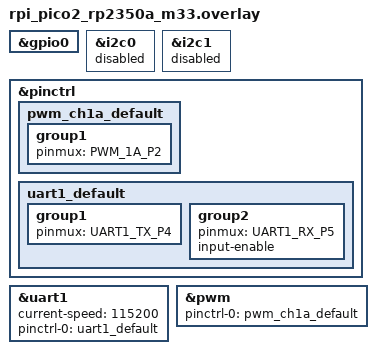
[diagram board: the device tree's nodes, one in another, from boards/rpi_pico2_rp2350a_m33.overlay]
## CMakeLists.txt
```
cmake_minimum_required(VERSION 3.20.0)

find_package(Zephyr REQUIRED HINTS $ENV{ZEPHYR_BASE})
project(blueline)

target_sources(app PRIVATE
	src/main.c
	src/fsm_main.c
	src/pico_io.c
	src/bt_uart.c
	src/bt_fsm.c
	src/bm_83.c
	src/slic.c
	src/ring.c
)
```

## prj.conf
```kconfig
CONFIG_GPIO=y
CONFIG_LOG=y
CONFIG_THREAD_NAME=y
CONFIG_PRINTK=y
CONFIG_SERIAL=y
CONFIG_UART_INTERRUPT_DRIVEN=y
CONFIG_PWM=y
CONFIG_EVENTS=y

# Log buffer: BM83 sends event bursts (one every ~5 ms) faster than the
# 115200 baud console can print them; 1024 (default) drops log messages
CONFIG_LOG_BUFFER_SIZE=8192
```

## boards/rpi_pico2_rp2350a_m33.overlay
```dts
/*
 * blueline - devicetree overlay for rpi_pico2/rp2350a/m33
 *
 * Only changes to the stock board devicetree are listed here. The stock board
 * already provides: gpio0, console on uart0 (GPIO0 TX / GPIO1 RX) and the user
 * LED led0 on GPIO25.
 *
 * GPIO usage of this project. The pins are configured at runtime in
 * src/pico_io.c, not through devicetree nodes:
 *
 *   GPIO2   POT_FWD_PIN      SLIC, PWM1 output (slice 1 A), 25 Hz, high = ringer off (src/ring.c)
 *   GPIO3   POT_PDOWN_N_PIN  SLIC power down, tristate after init (src/slic.c)
 *   GPIO6   BT_RST_N_PIN     output (BM83 reset, src/bm_83.c), low after init
 *   GPIO7   RING_MODE_PIN    SLIC, output, low after init (src/slic.c)
 *   GPIO8   BT_MFB_PIN       output (BM83 MFB, src/bm_83.c), low after init
 *   GPIO11  SHK_RISING_PIN   input, no pulls, IRQ on rising edge
 *   GPIO12  SHK_FALLING_PIN  input, no pulls, IRQ on falling edge
 *   GPIO25  PICO_IO_LED_PIN  output, user LED, high = on
 *
 * UART1 to the Microchip BM83 Bluetooth module (src/bt_uart.c):
 *
 *   GPIO4   UART1 TX  (RP2350 -> BM83)
 *   GPIO5   UART1 RX  (BM83 -> RP2350)
 *   115200 baud, 8N1, no flow control
 */

/* pico_io.c uses gpio0 directly (DT_NODELABEL(gpio0)) */
&gpio0 {
	status = "okay";
};

/* The stock board enables i2c0 (GPIO4/5) and i2c1 (GPIO6/7). These pins are
 * used here for UART1 and RING_MODE, so both I2C controllers are disabled. */
&i2c0 {
	status = "disabled";
};

&i2c1 {
	status = "disabled";
};

&pinctrl {
	/* ringer PWM: PWM slice 1 channel A on GP2 (POT_FWD) */
	pwm_ch1a_default: pwm_ch1a_default {
		group1 {
			pinmux = <PWM_1A_P2>;
		};
	};

	uart1_default: uart1_default {
		group1 {
			pinmux = <UART1_TX_P4>;
		};
		group2 {
			pinmux = <UART1_RX_P5>;
			input-enable;
		};
	};
};

/* BM83 link, no hw-flow-control property = no RTS/CTS */
&uart1 {
	status = "okay";
	current-speed = <115200>;
	pinctrl-0 = <&uart1_default>;
	pinctrl-names = "default";
};

/* Ringer PWM (src/ring.c). Replaces the board default pinctrl (PWM 4B on the
 * user LED GP25), so GP25 stays a GPIO. */
&pwm {
	status = "okay";
	pinctrl-0 = <&pwm_ch1a_default>;
	pinctrl-names = "default";
};
```

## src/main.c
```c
/*
 * blueline - main.c
 * Target: Raspberry Pi Pico 2 (RP2350), Zephyr RTOS
 * Initialises the I/O and creates all application threads.
 */

#include <zephyr/kernel.h>
#include <zephyr/logging/log.h>

#include "main.h"
#include "fsm_main.h"
#include "bt_fsm.h"
#include "pico_io.h"
#include "bt_uart.h"
#include "bm_83.h"
#include "slic.h"
#include "ring.h"

LOG_MODULE_REGISTER(main, LOG_LEVEL_INF);

/* ---- fsm_thread -------------------------------------------------------- */

K_THREAD_STACK_DEFINE(fsm_thread_stack, FSM_THREAD_STACK_SIZE);
static struct k_thread fsm_thread_data;
static k_tid_t fsm_thread_id;

/* ---- bt_fsm_thread ----------------------------------------------------- */

K_THREAD_STACK_DEFINE(bt_fsm_thread_stack, BT_FSM_THREAD_STACK_SIZE);
static struct k_thread bt_fsm_thread_data;
static k_tid_t bt_fsm_thread_id;

/* ---- bt_rx_thread ------------------------------------------------------ */

K_THREAD_STACK_DEFINE(bt_rx_thread_stack, BT_RX_THREAD_STACK_SIZE);
static struct k_thread bt_rx_thread_data;
static k_tid_t bt_rx_thread_id;

/* ---- ring_thread ------------------------------------------------------- */

K_THREAD_STACK_DEFINE(ring_thread_stack, RING_THREAD_STACK_SIZE);
static struct k_thread ring_thread_data;
static k_tid_t ring_thread_id;

/* ---- further threads will be added here -------------------------------- */

int main(void)
{
	LOG_INF("blueline starting");

	/* first: drive POT_FWD (GP2, PWM1) high as early as possible */
	if (ring_init() < 0) {
		LOG_ERR("ringer PWM init failed, stopping");
		return -1;
	}

	if (pico_io_init() < 0) {
		LOG_ERR("I/O init failed, stopping");
		return -1;
	}

	if (bt_uart_init() < 0) {
		LOG_ERR("BM83 UART init failed, stopping");
		return -1;
	}

	if (slic_init() < 0) {
		LOG_ERR("SLIC init failed, stopping");
		return -1;
	}


	fsm_thread_id = k_thread_create(&fsm_thread_data,
					fsm_thread_stack,
					K_THREAD_STACK_SIZEOF(fsm_thread_stack),
					fsm_main,
					NULL, NULL, NULL,
					FSM_THREAD_PRIORITY, 0, K_NO_WAIT);
	k_thread_name_set(fsm_thread_id, "fsm_thread");

	bt_fsm_thread_id = k_thread_create(&bt_fsm_thread_data,
					   bt_fsm_thread_stack,
					   K_THREAD_STACK_SIZEOF(bt_fsm_thread_stack),
					   bt_fsm_main,
					   NULL, NULL, NULL,
					   BT_FSM_THREAD_PRIORITY, 0, K_NO_WAIT);
	k_thread_name_set(bt_fsm_thread_id, "bt_fsm_thread");

	bt_rx_thread_id = k_thread_create(&bt_rx_thread_data,
					  bt_rx_thread_stack,
					  K_THREAD_STACK_SIZEOF(bt_rx_thread_stack),
					  bt_rx_main,
					  NULL, NULL, NULL,
					  BT_RX_THREAD_PRIORITY, 0, K_NO_WAIT);
	k_thread_name_set(bt_rx_thread_id, "bt_rx_thread");

	ring_thread_id = k_thread_create(&ring_thread_data,
					 ring_thread_stack,
					 K_THREAD_STACK_SIZEOF(ring_thread_stack),
					 generate_ring,
					 NULL, NULL, NULL,
					 RING_THREAD_PRIORITY, 0, K_NO_WAIT);
	k_thread_name_set(ring_thread_id, "ring_thread");

	/* BM83 power-up runs last: bt_rx_thread is already running and shows
	 * the BM83 responses (ACKs, status events) as they arrive. */
	if (IS_ENABLED(BT_UART_TX_DISABLE)) {
		/* BM83 is being programmed through J3: leave it alone */
		LOG_WRN("BT_UART_TX_DISABLE: bm83_init() skipped, GP6/GP8 not driven");
	} else if (bm83_init() < 0) {
		LOG_ERR("BM83 init failed");
		return -1;
	}

	/* main returns; the application threads keep running */
	return 0;
}
```

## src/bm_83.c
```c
/*
 * blueline - bm_83.c
 * Microchip BM83 Bluetooth module: control signals, power-up sequence and
 * commands sent over the UART (bt_uart.c).
 *
 * Power-up sequence (bm83_init):
 *   bt_rst_n = low, bt_mfb = low
 *   100 ms -> bt_mfb   = high
 *    20 ms -> bt_rst_n = high (BM83 out of reset)
 *   500 ms
 *   MMI action 0x51 (power on button press)
 *   MMI action 0x52 (power on button release)
 *   Read_BTM_Version (firmware version)
 *   MMI action 0x5D (enter pairing mode)
 *   bt_mfb = low
 *
 * MFB handshake: in host MCU mode MFB is the BM83 UART_RX_IND input
 * ("UART data from the MCU follows"), see Audio UART Command Set 4.1/4.4/4.5.
 *   command:    MFB high, >= 3 ms, send, wait for Command_ACK (max 200 ms),
 *               MFB low
 *   Event_ACK:  MFB high, >= 3 ms, send, MFB low (no reply)
 * Commands (main thread) and Event_ACKs (bt_rx_thread) can overlap, so MFB
 * is reference counted: high with the first user, low after the last one.
 *
 * The BM83 must be programmed with a host MCU mode configuration (UART
 * command interface enabled), otherwise it ignores all UART commands.
 */

#include <string.h>

#include <zephyr/kernel.h>
#include <zephyr/device.h>
#include <zephyr/drivers/gpio.h>
#include <zephyr/logging/log.h>

#include "bm_83.h"
#include "bt_uart.h"
#include "bt_fsm.h"

LOG_MODULE_REGISTER(bm_83, LOG_LEVEL_INF);

static const struct device *const gpio0 = DEVICE_DT_GET(DT_NODELABEL(gpio0));

/* ---- MFB handshake ----------------------------------------------------- */

K_MUTEX_DEFINE(mfb_mutex);
static uint8_t mfb_users;	/* senders that currently need MFB high */
static int64_t mfb_rise_ticks;	/* uptime when MFB went high */

/* MFB high (if not already) without waiting for the lead time */
static void bm83_mfb_raise(void)
{
	k_mutex_lock(&mfb_mutex, K_FOREVER);
	if (mfb_users++ == 0) {
		gpio_pin_set(gpio0, BT_MFB_PIN, 1);
		mfb_rise_ticks = k_uptime_ticks();
	}
	k_mutex_unlock(&mfb_mutex);
}

/* MFB high and wait until it has been high for BM83_MFB_LEAD_MS */
static void bm83_mfb_get(void)
{
	int64_t ready;
	int64_t now;

	bm83_mfb_raise();

	k_mutex_lock(&mfb_mutex, K_FOREVER);
	ready = mfb_rise_ticks + k_ms_to_ticks_ceil64(BM83_MFB_LEAD_MS);
	k_mutex_unlock(&mfb_mutex);

	now = k_uptime_ticks();
	if (now < ready) {
		k_sleep(K_TICKS(ready - now));
	}
}

/* Release MFB: low again when no other sender needs it */
static void bm83_mfb_put(void)
{
	k_mutex_lock(&mfb_mutex, K_FOREVER);
	if (mfb_users > 0 && --mfb_users == 0) {
		gpio_pin_set(gpio0, BT_MFB_PIN, 0);
	}
	k_mutex_unlock(&mfb_mutex);
}

/* ---- Command_ACK ------------------------------------------------------- */

/* Only one command at a time waits for its Command_ACK */
K_MUTEX_DEFINE(cmd_mutex);
K_SEM_DEFINE(cmd_ack_sem, 0, 1);
static bool cmd_ack_pending;
static uint8_t cmd_ack_id;	/* opcode of the command waiting for its ACK */
static uint8_t cmd_ack_status;

void bm83_command_ack_received(uint8_t cmd_id, uint8_t status)
{
	if (cmd_ack_pending && cmd_id == cmd_ack_id) {
		cmd_ack_status = status;
		cmd_ack_pending = false;

		/* Make_Call result goes to bt_fsm from here, so it is queued
		 * before the Call_Status events that follow the ACK */
		if (cmd_id == BM83_CMD_MAKE_CALL) {
			bt_fsm_post_event(status == BM83_ACK_COMMAND_COMPLETE ?
					  BT_EVT_CALL_ACK_OK : BT_EVT_CALL_ACK_FAIL);
		}

		k_sem_give(&cmd_ack_sem);
	}
}

/* ---- commands ---------------------------------------------------------- */

/* Build a frame for opcode and params */
static int bm83_build(uint8_t *frame, size_t size, uint8_t opcode,
		      const uint8_t *params, uint8_t num_params)
{
	int len;

	len = bt_uart_build_frame(frame, size, opcode, params, num_params);
	if (len < 0) {
		LOG_ERR("command 0x%02X: cannot build frame (%d)", opcode, len);
	}
	return len;
}

/* Send a command with the MFB handshake and wait for its Command_ACK.
 * Must not be called from bt_rx_thread (it delivers the Command_ACK).
 * Returns 0 on "command complete", -EIO for another ACK status,
 * -ETIMEDOUT if no Command_ACK arrives within BM83_CMD_ACK_TIMEOUT_MS. */
static int bm83_send_cmd(uint8_t opcode, const uint8_t *params, uint8_t num_params)
{
	uint8_t frame[BT_FRAME_MAX_LEN];
	int len;
	int ret;

	len = bm83_build(frame, sizeof(frame), opcode, params, num_params);
	if (len < 0) {
		return len;
	}

	k_mutex_lock(&cmd_mutex, K_FOREVER);

	k_sem_reset(&cmd_ack_sem);
	cmd_ack_id = opcode;
	cmd_ack_pending = true;

	bm83_mfb_get();
	bt_uart_send(frame, len);
	ret = k_sem_take(&cmd_ack_sem, K_MSEC(BM83_CMD_ACK_TIMEOUT_MS));
	bm83_mfb_put();

	cmd_ack_pending = false;

	if (ret != 0) {
		LOG_WRN("command 0x%02X: no Command_ACK within %d ms",
			opcode, BM83_CMD_ACK_TIMEOUT_MS);
		ret = -ETIMEDOUT;
	} else if (cmd_ack_status != BM83_ACK_COMMAND_COMPLETE) {
		LOG_WRN("command 0x%02X: Command_ACK status 0x%02X",
			opcode, cmd_ack_status);
		ret = -EIO;
	}

	k_mutex_unlock(&cmd_mutex);
	return ret;
}

int bm83_mmi_action(uint8_t action)
{
	const uint8_t params[] = { BM83_DATABASE_INDEX, action };

	LOG_INF("tx: MMI action 0x%02X", action);
	return bm83_send_cmd(BM83_CMD_MMI_ACTION, params, sizeof(params));
}

int bm83_enter_pairing(void)
{
	LOG_INF("tx: enter pairing mode");
	return bm83_mmi_action(BM83_MMI_ENTER_PAIRING);
}

int bm83_read_link_status(void)
{
	const uint8_t params[] = { 0x00 };	/* reserved */

	LOG_INF("tx: Read_Link_Status");
	return bm83_send_cmd(BM83_CMD_READ_LINK_STATUS, params, sizeof(params));
}

/* Print Read_Link_Status_Reply: device state, then per database the connected
 * profiles, play status and stream status */
static void bm83_log_link_status(const uint8_t *params, uint8_t num_params)
{
	static const char *const states[] = {
		"power off", "pairing", "standby", "connected (HF only)",
		"connected (A2DP only)", "connected (SPP only)",
		"connected (multi-profile)",
	};

	if (num_params < 3) {
		return;
	}

	LOG_INF("link status: device state 0x%02X %s", params[0],
		params[0] < ARRAY_SIZE(states) ? states[params[0]] : "unknown");

	for (uint8_t db = 0; db < 2; db++) {
		uint8_t con = params[1 + db];

		LOG_INF("link status: database %u: HF %s, A2DP %s/%s, AVRCP %s, SPP %s"
			" (0x%02X), play 0x%02X, stream 0x%02X",
			db,
			(con & BIT(3)) ? "yes" : "no",
			(con & BIT(0)) ? "sig" : "-",
			(con & BIT(1)) ? "stream" : "-",
			(con & BIT(2)) ? "yes" : "no",
			(con & BIT(4)) ? "yes" : "no",
			con,
			num_params > 3 + db ? params[3 + db] : 0,
			num_params > 5 + db ? params[5 + db] : 0);
	}
}

int bm83_end_call(void)
{
	LOG_INF("tx: end call");
	return bm83_mmi_action(BM83_MMI_END_CALL);
}

int bm83_accept_call(void)
{
	LOG_INF("tx: accept call");
	return bm83_mmi_action(BM83_MMI_ACCEPT_CALL);
}

int bm83_make_call(const char *number, uint8_t len)
{
	uint8_t params[1 + BM83_PHONE_NUMBER_MAX];

	if (len > BM83_PHONE_NUMBER_MAX) {
		LOG_ERR("Make_Call: number too long (%u digits)", len);
		return -EINVAL;
	}

	params[0] = BM83_DATABASE_INDEX;
	memcpy(&params[1], number, len);

	LOG_INF("tx: Make_Call \"%.*s\"", len, number);
	return bm83_send_cmd(BM83_CMD_MAKE_CALL, params, 1 + len);
}

void bm83_handle_event(uint8_t opcode, const uint8_t *params, uint8_t num_params)
{
	switch (opcode) {
	case BM83_EVT_BTM_STATUS:
		/* phone connected (HF or A2DP link): set the output gain */
		if (num_params >= 1 &&
		    (params[0] == BM83_STATUS_HF_LINK ||
		     params[0] == BM83_STATUS_A2DP_LINK)) {
			bm83_link_established();
		}
		break;
	case BM83_EVT_LINK_STATUS_REPLY:
		bm83_log_link_status(params, num_params);
		break;
	case BM83_EVT_CALL_STATUS:
		/* params: data_base_index, call status */
		if (num_params < 2) {
			break;
		}
		if (params[1] == BM83_CALL_OUTGOING || params[1] == BM83_CALL_ACTIVE) {
			bt_fsm_post_event(BT_EVT_CALL_OUTGOING);
		} else if (params[1] == BM83_CALL_IDLE) {
			bt_fsm_post_event(BT_EVT_CALL_IDLE);
		} else if (params[1] == BM83_CALL_INCOMING) {
			bt_fsm_post_event(BT_EVT_CALL_INCOMING);
		}
		break;
	default:
		break;
	}
}

int bm83_set_overall_gain(uint8_t mask, uint8_t type, uint8_t a2dp,
			  uint8_t hf, uint8_t line_in)
{
	const uint8_t params[] = { BM83_DATABASE_INDEX, mask, type,
				   a2dp, hf, line_in };

	LOG_INF("tx: Set_Overall_Gain mask 0x%02X type 0x%02X A2DP %u HF %u line-in %u",
		mask, type, a2dp, hf, line_in);
	return bm83_send_cmd(BM83_CMD_SET_OVERALL_GAIN, params, sizeof(params));
}

/* Runs in the system workqueue: may wait for the Command_ACK */
static void bm83_gain_work_handler(struct k_work *work)
{
	ARG_UNUSED(work);

	bm83_set_overall_gain(BM83_GAIN_MASK_A2DP | BM83_GAIN_MASK_HF,
			      BM83_GAIN_TYPE_ABS_LEVEL,
			      BM83_A2DP_GAIN_LEVEL, BM83_HF_GAIN_LEVEL, 0);
}

K_WORK_DEFINE(bm83_gain_work, bm83_gain_work_handler);

void bm83_link_established(void)
{
	k_work_submit(&bm83_gain_work);
}

int bm83_read_btm_version(uint8_t type)
{
	const uint8_t params[] = { type };

	LOG_INF("tx: Read_BTM_Version type 0x%02X", type);
	return bm83_send_cmd(BM83_CMD_READ_BTM_VERSION, params, sizeof(params));
}

int bm83_event_ack(uint8_t event_id)
{
	const uint8_t params[] = { event_id };
	uint8_t frame[BT_FRAME_MAX_LEN];
	int len;

	len = bm83_build(frame, sizeof(frame), BM83_CMD_EVENT_ACK,
			 params, sizeof(params));
	if (len < 0) {
		return len;
	}

	/* the BM83 does not answer an Event_ACK: MFB low right after sending */
	bm83_mfb_get();
	bt_uart_send(frame, len);
	bm83_mfb_put();

	LOG_DBG("tx: Event_ACK 0x%02X", event_id);
	return 0;
}

/* ---- init -------------------------------------------------------------- */

int bm83_init(void)
{
	int ret;

	if (!device_is_ready(gpio0)) {
		LOG_ERR("gpio0 not ready");
		return -ENODEV;
	}

	/* bt_rst_n: output, low (BM83 held in reset) */
	ret = gpio_pin_configure(gpio0, BT_RST_N_PIN, GPIO_OUTPUT_LOW);
	if (ret < 0) {
		LOG_ERR("bt_rst_n pin config failed (%d)", ret);
		return ret;
	}

	/* bt_mfb: output, low */
	ret = gpio_pin_configure(gpio0, BT_MFB_PIN, GPIO_OUTPUT_LOW);
	if (ret < 0) {
		LOG_ERR("bt_mfb pin config failed (%d)", ret);
		return ret;
	}

	/* MFB stays high from here through the power-up commands */
	k_msleep(BM83_MFB_HIGH_DELAY_MS);
	bm83_mfb_raise();

	k_msleep(BM83_RST_HIGH_DELAY_MS);
	gpio_pin_set(gpio0, BT_RST_N_PIN, 1);

	k_msleep(BM83_CMD_DELAY_MS);

	ret = bm83_mmi_action(BM83_MMI_POWER_ON_PRESS);
	if (ret == 0) {
		ret = bm83_mmi_action(BM83_MMI_POWER_ON_RELEASE);
	}
	if (ret == 0) {
		ret = bm83_read_btm_version(BM83_VERSION_FW);
	}
	if (ret == 0) {
		ret = bm83_enter_pairing();
	}

	/* end of the power-up sequence: MFB low unless an Event_ACK is going out */
	bm83_mfb_put();

	if (ret < 0) {
		return ret;
	}

	LOG_INF("BM83 initialised (GPIO%d bt_rst_n / GPIO%d bt_mfb)",
		BT_RST_N_PIN, BT_MFB_PIN);
	return 0;
}
```

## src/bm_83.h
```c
/*
 * blueline - bm_83.h
 * Microchip BM83 Bluetooth module: control signals, power-up sequence and
 * commands sent over the UART (bt_uart.c).
 */

#ifndef BM_83_H
#define BM_83_H

#include <stdint.h>
#include <zephyr/sys/util.h>

/* Pin assignment */
#define BT_RST_N_PIN   6   /* output, BM83 reset, active low */
#define BT_MFB_PIN     8   /* output, BM83 multi-function button */

/* Power-up sequence timing */
#define BM83_MFB_HIGH_DELAY_MS   100   /* init -> bt_mfb high */
#define BM83_RST_HIGH_DELAY_MS   20    /* bt_mfb high -> bt_rst_n high */
#define BM83_CMD_DELAY_MS        500   /* bt_rst_n high -> first command */

/* MFB handshake (Audio UART Command Set 4.4/4.5) */
#define BM83_MFB_LEAD_MS          3     /* bt_mfb high -> UART data (> 2 ms) */
#define BM83_CMD_ACK_TIMEOUT_MS   200   /* command -> Command_ACK */

/* Command opcodes */
#define BM83_CMD_MAKE_CALL       0x00
#define BM83_CMD_MMI_ACTION      0x02
#define BM83_CMD_READ_BTM_VERSION  0x08
#define BM83_CMD_READ_LINK_STATUS  0x0D
#define BM83_CMD_EVENT_ACK         0x14
#define BM83_CMD_SET_OVERALL_GAIN  0x23

/* Event opcodes */
#define BM83_EVT_COMMAND_ACK       0x00
#define BM83_EVT_BTM_STATUS        0x01
#define BM83_EVT_CALL_STATUS       0x02
#define BM83_EVT_LINK_STATUS_REPLY 0x1E

/* BTM_Status states that start the gain setting */
#define BM83_STATUS_HF_LINK        0x05   /* HF/HS link established */
#define BM83_STATUS_A2DP_LINK      0x06   /* A2DP link established */

/* Call_Status states */
#define BM83_CALL_IDLE             0x00   /* idle, no call */
#define BM83_CALL_INCOMING         0x02   /* incoming call */
#define BM83_CALL_OUTGOING         0x03   /* outgoing call */
#define BM83_CALL_ACTIVE           0x04   /* call active */

/* Database index of all commands with a Data_Base_Index parameter */
#define BM83_DATABASE_INDEX        0x00

/* Make_Call: maximum length of the phone number (ASCII digits) */
#define BM83_PHONE_NUMBER_MAX      19

/* Set_Overall_Gain: mask bits, type, levels */
#define BM83_GAIN_MASK_A2DP        BIT(0)
#define BM83_GAIN_MASK_HF          BIT(1)
#define BM83_GAIN_MASK_LINE_IN     BIT(2)
#define BM83_GAIN_TYPE_ABS_LEVEL   0x03   /* set absolute gain level 0..15 */
#define BM83_GAIN_LEVEL_MAX        0x0F

/* Gain levels set after the phone has connected (0..15) */
#define BM83_A2DP_GAIN_LEVEL       BM83_GAIN_LEVEL_MAX
#define BM83_HF_GAIN_LEVEL         BM83_GAIN_LEVEL_MAX

/* Command_ACK status */
#define BM83_ACK_COMMAND_COMPLETE  0x00

/* MMI actions */
#define BM83_MMI_POWER_ON_PRESS    0x51
#define BM83_MMI_POWER_ON_RELEASE  0x52
#define BM83_MMI_ENTER_PAIRING     0x5D   /* fast enter pairing mode (from non-off) */
#define BM83_MMI_ACCEPT_CALL       0x04   /* accept an incoming call */
#define BM83_MMI_END_CALL          0x06   /* end call / transfer audio to phone */

/* Read_BTM_Version types (reply: event 0x18 Read_BTM_Version_Reply) */
#define BM83_VERSION_UART          0x00
#define BM83_VERSION_FW            0x01

/* Initialise bt_rst_n and bt_mfb, run the power-up sequence, power the
 * BM83 on with MMI actions 0x51/0x52 and request its firmware version
 * (Read_BTM_Version) and put it into pairing mode. bt_mfb is low afterwards.
 * Blocks for about 650 ms.
 * Returns 0 on success, negative errno otherwise. */
int bm83_init(void);

/* Commands below are sent with the MFB handshake and wait for their
 * Command_ACK (max BM83_CMD_ACK_TIMEOUT_MS). They must not be called from
 * bt_rx_thread. Return 0 on "command complete", -EIO for another ACK status,
 * -ETIMEDOUT without ACK, other negative errno on errors. */

/* Send an MMI action command (opcode 0x02, data_base_index 0x00, action). */
int bm83_mmi_action(uint8_t action);

/* Put the BM83 into pairing mode (discoverable), MMI action 0x5D with a
 * pairing tone. Result: BTM_Status 0x01 (pairing), later 0x03 (pairing
 * successful) or 0x04 (pairing failed). */
int bm83_enter_pairing(void);

/* Set_Overall_Gain (opcode 0x23): data_base_index 0x00, mask (BM83_GAIN_MASK_*),
 * type (e.g. BM83_GAIN_TYPE_ABS_LEVEL), gain for A2DP, HF and line-in.
 * The phone may later change the gain again (AVRCP absolute volume). */
int bm83_set_overall_gain(uint8_t mask, uint8_t type, uint8_t a2dp,
			  uint8_t hf, uint8_t line_in);

/* Read_Link_Status (opcode 0x0D): the reply (event 0x1E) is decoded and
 * printed by bm83_handle_event(): device state and, per database, which
 * profiles (A2DP, AVRCP, HF, SPP) are connected. */
int bm83_read_link_status(void);

/* End the active call: MMI action 0x06 "End call / transfer audio to phone". */
int bm83_end_call(void);

/* Accept the incoming call: MMI action 0x04 "Accept an incoming call". */
int bm83_accept_call(void);

/* Make_Call (opcode 0x00): data_base_index 0x00, phone number as ASCII
 * digits (len <= BM83_PHONE_NUMBER_MAX). The Command_ACK result is also
 * posted to bt_fsm (BT_EVT_CALL_ACK_OK / BT_EVT_CALL_ACK_FAIL) by
 * bt_rx_thread. */
int bm83_make_call(const char *number, uint8_t len);

/* Called by bt_rx_thread for every received event except Command_ACK:
 * starts the gain setting when a link is established, forwards Call_Status
 * (incoming / outgoing / active / idle) to bt_fsm, prints Read_Link_Status_Reply. params[] are the event parameters. */
void bm83_handle_event(uint8_t opcode, const uint8_t *params, uint8_t num_params);

/* Called by bt_rx_thread when a link to the phone is established: sets
 * BM83_A2DP_GAIN_LEVEL / BM83_HF_GAIN_LEVEL from the system workqueue
 * (bt_rx_thread itself must not send commands). */
void bm83_link_established(void);

/* Send a Read_BTM_Version command (opcode 0x08) with the given type
 * (BM83_VERSION_UART or BM83_VERSION_FW). */
int bm83_read_btm_version(uint8_t type);

/* Acknowledge a received BM83 event (Event_ACK, opcode 0x14, param event_id).
 * Without it the BM83 waits 800 ms before it sends the next event
 * (Audio UART Command Set 4.5.2). Command_ACK events are not acknowledged.
 * Sent with the MFB handshake, does not wait for a reply.
 * Returns 0 on success, negative errno otherwise. */
int bm83_event_ack(uint8_t event_id);

/* Called by bt_rx_thread for every received Command_ACK: wakes up the
 * command waiting for it. */
void bm83_command_ack_received(uint8_t cmd_id, uint8_t status);

#endif /* BM_83_H */
```

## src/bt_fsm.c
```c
/*
 * blueline - bt_fsm.c
 * Bluetooth state machine running in bt_fsm_thread.
 *
 *   BT_IDLE            --BT_EVT_DIALCMPL-->       BT_MAKE_CALL
 *   BT_IDLE            --BT_EVT_CALL_INCOMING-->  BT_RING_MODE
 *   BT_RING_MODE       --BT_EVT_RING_PROTECT-->   BT_RING_BELL
 *   BT_RING_MODE       --BT_EVT_CALL_IDLE-->      BT_IDLE
 *   BT_RING_MODE       --BT_EVT_OFFHOOK-->        BT_OUT_ESTABLISHED  (RING_MODE low, MMI 0x04)
 *   BT_RING_BELL       --BT_EVT_OFFHOOK-->        BT_STOP_RING
 *   BT_RING_BELL       --BT_EVT_CALL_IDLE-->      BT_IDLE
 *   BT_STOP_RING       --BT_EVT_RING_PROTECT-->   BT_OUT_ESTABLISHED  (RING_MODE low, MMI 0x04)
 *   BT_STOP_RING       --BT_EVT_CALL_IDLE-->      BT_IDLE
 *   BT_MAKE_CALL       --BT_EVT_CALL_ACK_OK-->    BT_CALLER_WAIT
 *   BT_MAKE_CALL       --BT_EVT_CALL_ACK_FAIL-->  BT_NOHF
 *   BT_CALLER_WAIT     --BT_EVT_CALL_OUTGOING-->  BT_OUT_ESTABLISHED
 *   BT_CALLER_WAIT     --BT_EVT_MAIN_IDLE-->      BT_IDLE  (MMI 0x06 end call)
 *   BT_OUT_ESTABLISHED --BT_EVT_MAIN_IDLE-->      BT_IDLE  (MMI 0x06 end call)
 *   BT_OUT_ESTABLISHED --BT_EVT_CALL_IDLE-->      BT_IDLE
 *   every state except BT_IDLE  --BT_EVT_MAIN_IDLE-->  BT_IDLE
 *
 * Entry actions:
 *   BT_IDLE       RING_MODE_PIN low, ring_stop() (PWM_ON withdrawn)
 *   BT_MAKE_CALL  dialed_number_reg (fsm_main) as ASCII -> Make_Call (0x00)
 *   BT_RING_MODE  RING_MODE_PIN high, start ring_protect_timer (50 ms)
 *   BT_RING_BELL  ring_start() (PWM_ON: ring.c generates the cadence)
 *   BT_STOP_RING  ring_stop() (PWM_ON withdrawn, POT_FWD high at once),
 *                 start ring_protect_timer (50 ms)
 *
 * Event sources:
 *   BT_EVT_MAIN_IDLE      fsm_main, whenever it enters STATE_S0_IDLE
 *   BT_EVT_DIALCMPL       fsm_main, dialcmpl_timer expired in STATE_S1_OFFHOOK
 *   BT_EVT_CALL_ACK_OK    bt_rx_thread, Command_ACK of Make_Call, status 0x00
 *   BT_EVT_CALL_ACK_FAIL  bt_rx_thread, Command_ACK of Make_Call, status != 0x00;
 *                         bt_fsm itself if no Command_ACK arrives
 *   BT_EVT_CALL_OUTGOING  bt_rx_thread, Call_Status 0x03 or 0x04
 *   BT_EVT_CALL_IDLE      bt_rx_thread, Call_Status 0x00
 *   BT_EVT_CALL_INCOMING  bt_rx_thread, Call_Status 0x02
 *   BT_EVT_OFFHOOK        fsm_main, s0_idle -> s1_offhook (handset lifted)
 *   BT_EVT_RING_PROTECT   ring_protect_timer expired
 * The ACK result comes from bt_rx_thread (not from the return value of
 * bm83_make_call()) so it is queued before the Call_Status event that
 * follows the ACK.
 */

#include <errno.h>

#include <zephyr/kernel.h>
#include <zephyr/logging/log.h>

#include "bt_fsm.h"
#include "fsm_main.h"
#include "bm_83.h"
#include "slic.h"
#include "ring.h"

LOG_MODULE_REGISTER(bt_fsm, LOG_LEVEL_INF);

/* Event queue: filled by fsm_main and bt_rx_thread, emptied by bt_fsm_thread */
K_MSGQ_DEFINE(bt_fsm_event_q, sizeof(bt_fsm_event_t), 8, 4);

static bt_fsm_state_t current_state;

static const char *const state_names[BT_STATE_COUNT] = {
	[BT_IDLE]            = "bt_idle",
	[BT_MAKE_CALL]       = "bt_make_call",
	[BT_CALLER_WAIT]     = "bt_caller_wait",
	[BT_NOHF]            = "bt_nohf",
	[BT_OUT_ESTABLISHED] = "bt_out_established",
	[BT_RING_BELL]       = "bt_ring_bell",
	[BT_RING_MODE]       = "bt_ring_mode",
	[BT_STOP_RING]       = "bt_stop_ring",
};

/* ---- RING_PROTECT timer ------------------------------------------------ */

/* Timer expiry function runs in ISR context: only post an event */
static void ring_protect_expired(struct k_timer *timer)
{
	ARG_UNUSED(timer);
	bt_fsm_post_event(BT_EVT_RING_PROTECT);
}

K_TIMER_DEFINE(ring_protect_timer, ring_protect_expired, NULL);

/* A stopped or restarted timer has time left / no time left: used to ignore
 * stale BT_EVT_RING_PROTECT events from an earlier run */
static bool ring_protect_expired_now(void)
{
	return k_timer_remaining_ticks(&ring_protect_timer) == 0;
}

/* ---- helpers ----------------------------------------------------------- */

void bt_fsm_post_event(bt_fsm_event_t ev)
{
	/* K_NO_WAIT: safe to call from an ISR; event is dropped if the queue is full */
	if (k_msgq_put(&bt_fsm_event_q, &ev, K_NO_WAIT) != 0) {
		LOG_WRN("event queue full, event %d dropped", ev);
	}
}

bt_fsm_state_t bt_fsm_get_state(void)
{
	return current_state;
}

/* Send dialed_number_reg as Make_Call. Digits are pulse counts: 10 = '0'. */
static void bt_fsm_make_call(void)
{
	uint8_t digits[NUMBER_ARRAY_SIZE];
	char number[NUMBER_ARRAY_SIZE];
	uint8_t len;
	uint8_t n = 0;
	int ret;

	len = fsm_get_dialed_number(digits, sizeof(digits));

	for (uint8_t i = 0; i < len; i++) {
		if (digits[i] >= 1 && digits[i] <= 9) {
			number[n++] = '0' + digits[i];
		} else if (digits[i] == 10) {
			number[n++] = '0';
		} else {
			LOG_WRN("invalid digit %u at position %u skipped", digits[i], i);
		}
	}

	/* debug: show which profiles are connected before calling */
	bm83_read_link_status();

	ret = bm83_make_call(number, n);

	/* With a Command_ACK, bt_rx_thread has already posted the result */
	if (ret == -ETIMEDOUT || (ret < 0 && ret != -EIO)) {
		bt_fsm_post_event(BT_EVT_CALL_ACK_FAIL);
	}
}

/* Answer the incoming call: ring mode off, accept call */
static void bt_fsm_answer_call(void)
{
	k_timer_stop(&ring_protect_timer);
	slic_ring_mode_set(false);
	bm83_accept_call();
}

/* Change state and execute the entry action of the new state */
static void bt_fsm_enter_state(bt_fsm_state_t new_state)
{
	LOG_INF("state %s -> %s",
		state_names[current_state], state_names[new_state]);
	current_state = new_state;

	switch (new_state) {
	case BT_IDLE:
		k_timer_stop(&ring_protect_timer);
		ring_stop();
		slic_ring_mode_set(false);
		break;
	case BT_MAKE_CALL:
		bt_fsm_make_call();
		break;
	case BT_RING_MODE:
		slic_ring_mode_set(true);
		k_timer_start(&ring_protect_timer, K_MSEC(RING_PROTECT_MS), K_NO_WAIT);
		break;
	case BT_RING_BELL:
		ring_start();
		break;
	case BT_STOP_RING:
		ring_stop();
		k_timer_start(&ring_protect_timer, K_MSEC(RING_PROTECT_MS), K_NO_WAIT);
		break;
	default:
		break;
	}
}

/* ---- state handlers ---------------------------------------------------- */

static void state_bt_idle(bt_fsm_event_t ev)
{
	switch (ev) {
	case BT_EVT_DIALCMPL:
		bt_fsm_enter_state(BT_MAKE_CALL);
		break;
	case BT_EVT_CALL_INCOMING:
		bt_fsm_enter_state(BT_RING_MODE);
		break;
	default:
		break;
	}
}

static void state_bt_make_call(bt_fsm_event_t ev)
{
	switch (ev) {
	case BT_EVT_MAIN_IDLE:
		bt_fsm_enter_state(BT_IDLE);
		break;
	case BT_EVT_CALL_ACK_OK:
		bt_fsm_enter_state(BT_CALLER_WAIT);
		break;
	case BT_EVT_CALL_ACK_FAIL:
		bt_fsm_enter_state(BT_NOHF);
		break;
	default:
		break;
	}
}

static void state_bt_caller_wait(bt_fsm_event_t ev)
{
	switch (ev) {
	case BT_EVT_MAIN_IDLE:
		/* handset on hook while the phone is dialling: end the call */
		bm83_end_call();
		bt_fsm_enter_state(BT_IDLE);
		break;
	case BT_EVT_CALL_OUTGOING:
		bt_fsm_enter_state(BT_OUT_ESTABLISHED);
		break;
	default:
		break;
	}
}

static void state_bt_nohf(bt_fsm_event_t ev)
{
	switch (ev) {
	case BT_EVT_MAIN_IDLE:
		bt_fsm_enter_state(BT_IDLE);
		break;
	default:
		break;
	}
}

static void state_bt_out_established(bt_fsm_event_t ev)
{
	switch (ev) {
	case BT_EVT_MAIN_IDLE:
		/* handset on hook: end the call on the phone */
		bm83_end_call();
		bt_fsm_enter_state(BT_IDLE);
		break;
	case BT_EVT_CALL_IDLE:
		/* the call has ended (e.g. the other side hung up) */
		bt_fsm_enter_state(BT_IDLE);
		break;
	default:
		break;
	}
}

static void state_bt_ring_mode(bt_fsm_event_t ev)
{
	switch (ev) {
	case BT_EVT_RING_PROTECT:
		if (ring_protect_expired_now()) {
			bt_fsm_enter_state(BT_RING_BELL);
		}
		break;
	case BT_EVT_CALL_IDLE:
		/* caller hung up before ringing started */
		bt_fsm_enter_state(BT_IDLE);
		break;
	case BT_EVT_OFFHOOK:
		/* handset lifted before ringing started: answer at once */
		bt_fsm_answer_call();
		bt_fsm_enter_state(BT_OUT_ESTABLISHED);
		break;
	default:
		break;
	}
}

static void state_bt_ring_bell(bt_fsm_event_t ev)
{
	switch (ev) {
	case BT_EVT_OFFHOOK:
		/* handset lifted: stop ringing */
		bt_fsm_enter_state(BT_STOP_RING);
		break;
	case BT_EVT_CALL_IDLE:
		/* caller hung up before the handset was lifted */
		bt_fsm_enter_state(BT_IDLE);
		break;
	default:
		break;
	}
}

static void state_bt_stop_ring(bt_fsm_event_t ev)
{
	switch (ev) {
	case BT_EVT_RING_PROTECT:
		if (ring_protect_expired_now()) {
			/* ringer settled: ring mode off, answer the incoming call */
			bt_fsm_answer_call();
			bt_fsm_enter_state(BT_OUT_ESTABLISHED);
		}
		break;
	case BT_EVT_CALL_IDLE:
		/* caller hung up while the ringer was stopping */
		bt_fsm_enter_state(BT_IDLE);
		break;
	default:
		break;
	}
}

/* ---- thread entry ------------------------------------------------------ */

void bt_fsm_main(void *p1, void *p2, void *p3)
{
	ARG_UNUSED(p1);
	ARG_UNUSED(p2);
	ARG_UNUSED(p3);

	bt_fsm_event_t ev;

	/* After power up bt_fsm starts in BT_IDLE */
	current_state = BT_IDLE;
	LOG_INF("bt_fsm_thread started, state %s", state_names[current_state]);

	while (1) {
		/* Sleep until an event arrives - no polling */
		k_msgq_get(&bt_fsm_event_q, &ev, K_FOREVER);

		switch (current_state) {
		case BT_IDLE:
			state_bt_idle(ev);
			break;
		case BT_MAKE_CALL:
			state_bt_make_call(ev);
			break;
		case BT_CALLER_WAIT:
			state_bt_caller_wait(ev);
			break;
		case BT_NOHF:
			state_bt_nohf(ev);
			break;
		case BT_OUT_ESTABLISHED:
			state_bt_out_established(ev);
			break;
		case BT_RING_BELL:
			state_bt_ring_bell(ev);
			break;
		case BT_RING_MODE:
			state_bt_ring_mode(ev);
			break;
		case BT_STOP_RING:
			state_bt_stop_ring(ev);
			break;
		default:
			LOG_ERR("invalid state %d, back to bt_idle", current_state);
			bt_fsm_enter_state(BT_IDLE);
			break;
		}
	}
}
```

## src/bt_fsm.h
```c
/*
 * blueline - bt_fsm.h
 * Bluetooth state machine running in bt_fsm_thread.
 */

#ifndef BT_FSM_H
#define BT_FSM_H

/* RING_PROTECT timer: settle time around ring mode switching */
#define RING_PROTECT_MS   50

/* bt_fsm states */
typedef enum {
	BT_IDLE = 0,
	BT_MAKE_CALL,
	BT_CALLER_WAIT,
	BT_NOHF,
	BT_OUT_ESTABLISHED,
	BT_RING_BELL,
	BT_RING_MODE,
	BT_STOP_RING,
	BT_STATE_COUNT
} bt_fsm_state_t;

/* Events delivered to bt_fsm */
typedef enum {
	BT_EVT_MAIN_IDLE = 0,	/* fsm_main entered STATE_S0_IDLE */
	BT_EVT_DIALCMPL,	/* dialcmpl_timer expired while fsm_main in STATE_S1_OFFHOOK */
	BT_EVT_CALL_ACK_OK,	/* Command_ACK of Make_Call with status 0x00 */
	BT_EVT_CALL_ACK_FAIL,	/* Command_ACK of Make_Call with status != 0x00, or no ACK */
	BT_EVT_CALL_OUTGOING,	/* Call_Status: outgoing call (0x03) or call active (0x04) */
	BT_EVT_CALL_IDLE,	/* Call_Status: idle (0x00), the call has ended */
	BT_EVT_CALL_INCOMING,	/* Call_Status: incoming call (0x02) */
	BT_EVT_OFFHOOK,		/* fsm_main: s0_idle -> s1_offhook (handset lifted) */
	BT_EVT_RING_PROTECT,	/* ring_protect_timer expired */
	BT_EVT_COUNT
} bt_fsm_event_t;

/* Entry point of bt_fsm_thread (signature as required by k_thread_create). */
void bt_fsm_main(void *p1, void *p2, void *p3);

/* Hand an event to bt_fsm. ISR-safe, never blocks. */
void bt_fsm_post_event(bt_fsm_event_t ev);

/* Returns the current bt_fsm state. */
bt_fsm_state_t bt_fsm_get_state(void);

#endif /* BT_FSM_H */
```

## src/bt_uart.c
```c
/*
 * blueline - bt_uart.c
 * UART1 link to the Microchip BM83 Bluetooth module (115200 baud, 8N1,
 * no flow control, TX = GPIO4, RX = GPIO5).
 *
 * Transmit: bt_uart_build_frame() builds a frame, bt_uart_send() sends it
 * (mutex protected, it is used by several threads).
 * The BM83 commands themselves are in bm_83.c.
 *
 * Receive: the UART interrupt bt_uart_isr collects the bytes of one frame
 * and hands the complete raw frame to bt_rx_thread through bt_rx_q.
 * bt_rx_thread checks the checksum first, then stores header, opcode and
 * parameters in rx_buffer (rest filled with 0x00) and prints them together
 * with the BM83 event name of the opcode. Every event except Command_ACK is
 * acknowledged with Event_ACK (bm83_event_ack()).
 */

#include <string.h>

#include <zephyr/kernel.h>
#include <zephyr/device.h>
#include <zephyr/drivers/uart.h>
#include <zephyr/drivers/gpio.h>
#include <zephyr/logging/log.h>

#include "bt_uart.h"
#include "bm_83.h"

LOG_MODULE_REGISTER(bt_uart, LOG_LEVEL_INF);

static const struct device *const bt_uart = DEVICE_DT_GET(DT_NODELABEL(uart1));

/* Complete raw frames: filled by bt_uart_isr, emptied by bt_rx_thread */
K_MSGQ_DEFINE(bt_rx_q, BT_UART_RX_BUF_SIZE, 4, 1);

/* Receive buffer array: header, opcode, parameters, rest 0x00 */
static uint8_t rx_buffer[BT_UART_RX_BUF_SIZE];

/* ---- checksum ---------------------------------------------------------- */

/* checksum = 1 + ~(length(h) + length(l) + opcode + parameters).
 * bytes[] starts at length(h), n = number of bytes to add up. */
static uint8_t bt_uart_checksum(const uint8_t *bytes, size_t n)
{
	uint8_t sum = 0;

	for (size_t i = 0; i < n; i++) {
		sum += bytes[i];
	}

	return (uint8_t)(1 + ~sum);
}

/* ---- transmit ---------------------------------------------------------- */

int bt_uart_build_frame(uint8_t *frame, size_t size, uint8_t opcode,
			const uint8_t *params, uint8_t num_params)
{
	uint16_t length = 1 + num_params;	/* opcode + parameters */
	size_t frame_len = 4 + num_params + 1;

	if (num_params > BT_FRAME_MAX_PARAMS || size < frame_len) {
		return -EINVAL;
	}

	frame[0] = BT_FRAME_HEADER;
	frame[1] = length >> 8;
	frame[2] = length & 0xFF;
	frame[3] = opcode;
	for (uint8_t i = 0; i < num_params; i++) {
		frame[4 + i] = params[i];
	}
	/* checksum over length(h) .. last parameter */
	frame[frame_len - 1] = bt_uart_checksum(&frame[1], frame_len - 2);

	return frame_len;
}

/* bt_uart_send() is called from several threads (main: commands,
 * bt_rx_thread: Event_ACK); the mutex keeps the frames from mixing */
K_MUTEX_DEFINE(bt_tx_mutex);

void bt_uart_send(const uint8_t *data, size_t len)
{
	if (IS_ENABLED(BT_UART_TX_DISABLE)) {
		return;		/* TX pin is tristate */
	}

	k_mutex_lock(&bt_tx_mutex, K_FOREVER);
	for (size_t i = 0; i < len; i++) {
		uart_poll_out(bt_uart, data[i]);
	}
	k_mutex_unlock(&bt_tx_mutex);
}

/* ---- receive ----------------------------------------------------------- */

/* BM83 UART event names, indexed by opcode (NULL = not defined) */
static const char *const bm83_event_names[] = {
	[0x00] = "Command_ACK",
	[0x01] = "BTM_Status",
	[0x02] = "Call_Status",
	[0x03] = "Caller_ID",
	[0x04] = "SMS_Received_Indication",
	[0x05] = "Missed_Call_Indication",
	[0x06] = "Phone_Max_Battery_Level",
	[0x07] = "Phone_Current_Battery_Level",
	[0x08] = "Roaming_Status",
	[0x09] = "Phone_Max_Signal_Strength_Level",
	[0x0A] = "Phone_Current_Signal_Strength_Level",
	[0x0B] = "Phone_Service_Status",
	[0x0C] = "BTM_Battery_Status",
	[0x0D] = "BTM_Charging_Status",
	[0x0E] = "Reset_To_Default",
	[0x0F] = "Report_HF_Gain_Level",
	[0x10] = "EQ_Mode_Indication",
	[0x17] = "Read_Linked_Device_Information_Reply",
	[0x18] = "Read_BTM_Version_Reply",
	[0x19] = "Call_List_Report",
	[0x1A] = "AVC_Specific_Rsp",
	[0x1B] = "BTM_Utility_Req",
	[0x1C] = "Vendor_AT_Cmd_Reply",
	[0x1D] = "Report_Vendor_AT_Event",
	[0x1E] = "Read_Link_Status_Reply",
	[0x1F] = "Read_Paired_Device_Record_Reply",
	[0x20] = "Read_Local_BD_Address_Reply",
	[0x21] = "Read_Local_Device_Name_Reply",
	[0x22] = "Report_SPP/iAP_Data",
	[0x23] = "Report_Link_Back_Status",
	[0x24] = "REPORT_RING_TONE_STATUS",
	[0x25] = "User_Confrim_SSP_Req",
	[0x26] = "Report_AVRCP_Vol_Ctrl",
	[0x27] = "Report_Input_Signal_Level",
	[0x28] = "Report_iAP_Info",
	[0x29] = "REPORT_AVRCP_ABS_VOL_CTRL",
	[0x2A] = "Report_Voice_Prompt_Status",
	[0x2D] = "Report_Type_Codec",
	[0x2E] = "Report_Type_BTM_Setting",
	[0x2F] = "Report_MCU_Update_Reply",
	[0x30] = "Report_BTM_Initial_Status",
	[0x31] = "LE_ANCS_Service_Event",
	[0x32] = "LE_Signaling_Event",
	[0x33] = "Report_nSPK_Link_Status",
	[0x34] = "Report_nSPK_Vendor_Event",
	[0x35] = "Report_nSPK_Audio_Setting",
	[0x36] = "Report_Sound_Effect_Status",
	[0x37] = "Report_Vendor_EEPROM_Data",
	[0x38] = "REPORT_IC_VERSION_INFO",
	[0x39] = "REPORT_LE_GATT_EVENT",
	[0x3A] = "Report_BTM_Link_Mode",
	[0x3B] = "DSP_Dedicated_Event",
	[0x3C] = "Report_nSPK_MISC_Event",
	[0x3D] = "Report_nSPK_Exchange_Link_Info",
	[0x3E] = "Report_Customized_Information",
	[0x3F] = "Report_CSB_CLK",
	[0x40] = "Report_Read_Feature_List_Reply",
	[0x41] = "REPORT_TEST_RESULT_REPLY",
	[0x42] = "Report_Read_EEPROM_Data",
	[0x43] = "PBAPC_Event",
	[0x44] = "AVRCP_Browsing_Event",
};

/* Name of a BM83 event opcode, "unknown" if not in the list */
static const char *bm83_event_name(uint8_t opcode)
{
	if (opcode < ARRAY_SIZE(bm83_event_names) && bm83_event_names[opcode] != NULL) {
		return bm83_event_names[opcode];
	}
	return "unknown";
}

/* Raw frame being collected by the ISR: header, length, opcode, params, checksum */
static uint8_t rx_raw[BT_UART_RX_BUF_SIZE];
static uint8_t rx_pos;
static uint8_t rx_frame_len;

/* Feed one received byte into the frame collector (ISR context) */
static void bt_uart_rx_byte(uint8_t byte)
{
	if (rx_pos == 0) {
		/* wait for the header, ignore fill bytes (0x00) between frames */
		if (byte == BT_FRAME_HEADER) {
			rx_raw[rx_pos++] = byte;
		}
		return;
	}

	rx_raw[rx_pos++] = byte;

	if (rx_pos == 3) {
		uint16_t length = (rx_raw[1] << 8) | rx_raw[2];

		if (length < 1 || length > 1 + BT_FRAME_MAX_PARAMS) {
			LOG_WRN("rx: invalid length %u, frame dropped", length);
			rx_pos = 0;
			return;
		}
		/* header + length(h) + length(l) + length + checksum */
		rx_frame_len = 3 + length + 1;
	} else if (rx_pos > 3 && rx_pos == rx_frame_len) {
		if (k_msgq_put(&bt_rx_q, rx_raw, K_NO_WAIT) != 0) {
			LOG_WRN("rx: queue full, frame dropped");
		}
		rx_pos = 0;
	}
}

static void bt_uart_isr(const struct device *dev, void *user_data)
{
	ARG_UNUSED(user_data);
	uint8_t byte;

	if (!uart_irq_update(dev)) {
		return;
	}

	while (uart_irq_rx_ready(dev) && uart_fifo_read(dev, &byte, 1) == 1) {
		bt_uart_rx_byte(byte);
	}
}

/* Check one raw frame, store it in rx_buffer and print it */
static void bt_uart_rx_frame(const uint8_t *raw)
{
	uint16_t length = (raw[1] << 8) | raw[2];
	uint8_t num_params = length - 1;
	uint8_t checksum = raw[3 + length];
	uint8_t expected = bt_uart_checksum(&raw[1], 2 + length);
	char buf[BT_FRAME_MAX_PARAMS * 5 + 1];	/* "0xAA " per parameter */
	int len = 0;

	/* the checksum is checked before opcode and parameters are used */
	if (checksum != expected) {
		LOG_ERR("rx: checksum error, received 0x%02X, expected 0x%02X",
			checksum, expected);
		return;
	}

	memset(rx_buffer, 0x00, sizeof(rx_buffer));
	rx_buffer[0] = raw[0];			/* header */
	rx_buffer[1] = raw[3];			/* opcode */
	memcpy(&rx_buffer[2], &raw[4], num_params);

	buf[0] = '\0';
	for (uint8_t i = 0; i < num_params; i++) {
		len += snprintk(&buf[len], sizeof(buf) - len, "0x%02X ",
				rx_buffer[2 + i]);
	}

	LOG_INF("rx: %s | checksum 0x%02X | opcode 0x%02X | params %s",
		bm83_event_name(rx_buffer[1]), checksum, rx_buffer[1], buf);

	if (rx_buffer[1] == BM83_EVT_COMMAND_ACK) {
		/* params: command id, status -> wake up the waiting command */
		if (num_params >= 2) {
			bm83_command_ack_received(rx_buffer[2], rx_buffer[3]);
		}
	} else {
		/* acknowledge every other event, so the BM83 sends the next
		 * event right away instead of after its 800 ms timeout */
		bm83_event_ack(rx_buffer[1]);

		/* react to the event (gain setting, call status for bt_fsm) */
		bm83_handle_event(rx_buffer[1], &rx_buffer[2], num_params);
	}
}

void bt_rx_main(void *p1, void *p2, void *p3)
{
	ARG_UNUSED(p1);
	ARG_UNUSED(p2);
	ARG_UNUSED(p3);

	uint8_t raw[BT_UART_RX_BUF_SIZE];

	while (1) {
		/* Sleep until the ISR has collected a complete frame */
		k_msgq_get(&bt_rx_q, raw, K_FOREVER);
		bt_uart_rx_frame(raw);
	}
}

/* ---- init -------------------------------------------------------------- */

int bt_uart_init(void)
{
	int ret;

	if (!device_is_ready(bt_uart)) {
		LOG_ERR("uart1 not ready");
		return -ENODEV;
	}

	ret = uart_irq_callback_user_data_set(bt_uart, bt_uart_isr, NULL);
	if (ret < 0) {
		LOG_ERR("uart1 IRQ callback failed (%d)", ret);
		return ret;
	}
	uart_irq_rx_enable(bt_uart);
	if (IS_ENABLED(BT_UART_TX_DISABLE)) {
		/* Take GP4 away from UART1: GPIO input, no pulls = tristate */
		ret = gpio_pin_configure(DEVICE_DT_GET(DT_NODELABEL(gpio0)),
					 BT_UART_TX_PIN, GPIO_INPUT);
		if (ret < 0) {
			LOG_ERR("GP%d tristate config failed (%d)", BT_UART_TX_PIN, ret);
			return ret;
		}
		LOG_WRN("uart1 TX disabled, GP%d is tristate (BT_UART_TX_DISABLE)",
			BT_UART_TX_PIN);
	}

	LOG_INF("uart1 (BM83) initialised");
	return 0;
}
```

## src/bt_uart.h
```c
/*
 * blueline - bt_uart.h
 * UART1 link to the Microchip BM83 Bluetooth module: frame build/send and
 * frame receive.
 *
 * Frame format (both directions):
 *   0xAA | length(h) | length(l) | opcode | parameters (0..20) | checksum
 *   length   = 1 (opcode) + number of parameter bytes
 *   checksum = 1 + ~(length(h) + length(l) + opcode + parameters)
 * Bytes between frames (e.g. 0x00) are ignored until the next 0xAA.
 */

#ifndef BT_UART_H
#define BT_UART_H

#include <stddef.h>
#include <stdint.h>

#define BT_FRAME_HEADER      0xAA
#define BT_FRAME_MAX_PARAMS  20

/* Longest frame: header + length(h) + length(l) + opcode + params + checksum */
#define BT_FRAME_MAX_LEN     (4 + BT_FRAME_MAX_PARAMS + 1)

/* UART1 TX pin (RP2350 -> BM83 UART_RXD, pin 29) */
#define BT_UART_TX_PIN       4

/* Programming the BM83 with isUpdate (USB-UART adapter on J3):
 * 1 = GP4 is switched to a GPIO input without pulls (tristate) so the adapter
 *     can drive the BM83 RX line, bt_uart_send() sends nothing, and main()
 *     skips bm83_init() so GP6 (reset) and GP8 (MFB) stay undriven inputs.
 *     Receiving on GP5 still works.
 * 0 = normal operation. */
#define BT_UART_TX_DISABLE   0

/* Size of the receive buffer array */
#define BT_UART_RX_BUF_SIZE  32

/* Initialise UART1 and enable the receive interrupt.
 * Returns 0 on success, negative errno otherwise. */
int bt_uart_init(void);

/* Build a complete frame (header, length, opcode, parameters, checksum) in
 * frame[]. Returns the frame length in bytes, or -EINVAL if num_params is too
 * large or frame[] is too small. */
int bt_uart_build_frame(uint8_t *frame, size_t size, uint8_t opcode,
			const uint8_t *params, uint8_t num_params);

/* Send len bytes on UART1 (blocking). */
void bt_uart_send(const uint8_t *data, size_t len);

/* Entry point of bt_rx_thread: checks and prints received frames. */
void bt_rx_main(void *p1, void *p2, void *p3);

#endif /* BT_UART_H */
```

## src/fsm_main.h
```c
/*
 * blueline - fsm_main.h
 * State machine running in fsm_thread.
 */

#ifndef FSM_MAIN_H
#define FSM_MAIN_H

#include <stdint.h>

/* FSM timer timeouts */
#define PULSE_TIMER_MS    100   /* > make time between dial pulses (~44 ms) */
#define HANGUP_TIMER_MS   100
#define DIALCMPL_TIMER_MS 3000

/* Maximum number of dialled digits stored in number_array */
#define NUMBER_ARRAY_SIZE 19

/* FSM states */
typedef enum {
	STATE_S0_IDLE = 0,
	STATE_S1_OFFHOOK,
	STATE_S2_OPEN,
	STATE_S3_CLOSED,
	STATE_COUNT
} fsm_state_t;

/* Events delivered to the FSM (from ISRs and timer expiry functions) */
typedef enum {
	EVT_SHK_ACTIVE = 0,
	EVT_SHK_INACTIVE,
	EVT_PULSE_TIMEOUT,
	EVT_HANGUP_TIMEOUT,
	EVT_DIALCMPL,
	FSM_EV_COUNT
} fsm_event_t;

/* Entry point of fsm_thread (signature as required by k_thread_create). */
void fsm_main(void *p1, void *p2, void *p3);

/* Hand an event to the FSM. ISR-safe, never blocks. */
void fsm_post_event(fsm_event_t ev);

/* Returns the current state (for debugging / other threads later). */
fsm_state_t fsm_get_state(void);

/* Copy dialed_number_reg (pulse counts, 10 = digit 0) to digits[] (at most
 * size entries). Returns the number of digits. */
uint8_t fsm_get_dialed_number(uint8_t *digits, uint8_t size);

#endif /* FSM_MAIN_H */
```

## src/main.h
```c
/*
 * blueline - main.h
 * Thread configuration.
 */

#ifndef MAIN_H
#define MAIN_H

/* fsm_thread */
#define FSM_THREAD_STACK_SIZE  2048
#define FSM_THREAD_PRIORITY    5

/* bt_fsm_thread: Bluetooth state machine */
#define BT_FSM_THREAD_STACK_SIZE  1024
#define BT_FSM_THREAD_PRIORITY    6

/* bt_rx_thread: checks and prints frames received from the BM83 */
#define BT_RX_THREAD_STACK_SIZE  1024
#define BT_RX_THREAD_PRIORITY    6

/* ring_thread: ring cadence generator */
#define RING_THREAD_STACK_SIZE   1024
#define RING_THREAD_PRIORITY     7

#endif /* MAIN_H */
```

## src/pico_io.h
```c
/*
 * blueline - pico_io.h
 * GPIO setup for the Raspberry Pi Pico 2 (RP2350): shk and user LED.
 */

#ifndef PICO_IO_H
#define PICO_IO_H

#include <stdbool.h>

/* Pin assignment */
#define SHK_FALLING_PIN   12   /* shk, input, IRQ on falling edge */
#define SHK_RISING_PIN    11   /* shk, input, IRQ on rising edge */
#define PICO_IO_LED_PIN   25   /* user LED on the Pico 2, active high */

/* Time after an shk edge at which the pin level is checked */
#define SHK_CHECK_MS      20

/* Initialise shk pins (input without pulls, edge IRQs) and LED (output, off).
 * Returns 0 on success, negative errno otherwise. */
int pico_io_init(void);

/* Switch the user LED on (true) or off (false). */
void pico_io_led_set(bool on);

#endif /* PICO_IO_H */
```
